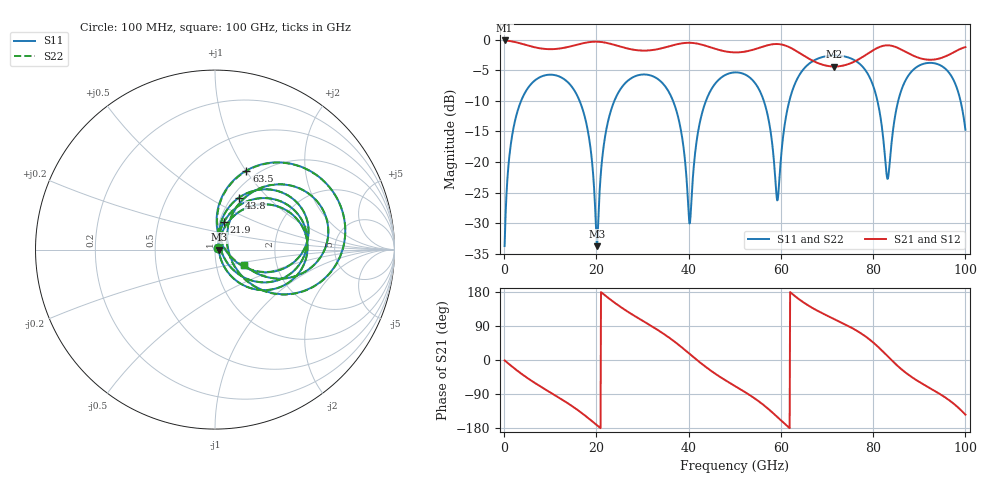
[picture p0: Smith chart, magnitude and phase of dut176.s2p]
! Touchstone file exported from HFSS 2026.1.0
!  File:  C:/ffzhzh/LocalFiles/Ansys_Project_Files/temp_test_TSV_RDL_176_1783474584_48356.aedt
!  Generated:  09:47:24 AM Jul  8, 2026
!  Design:  TSV_RDL
!  Project:  temp_test_TSV_RDL_176_1783474584_48356
! Variables:
!  h_bsmrdl = 3.29um
!  h_ox = 20um
!  h_rdl = 5um
!  h_sub = 71.26um
!  h_tmrdl = 2.49um
!  h_tsv = 71.26um
!  h_via = 3um
!  l_bsmrdl = 349.83um
!  l_sub = 2814um
!  l_tmrdl = 313.58um
!  m_sub = 200um
!  pitch = 45.72um
!  r_tsv = 9.64um
!  s_tmrdl = 10um
!  w_bsmrdl = 20.47um
!  w_sub = 500um
!  w_tmrdl = 16.26um
!  x_tsv_center1 = 321.71um
!  x_tsv_center2 = 692.01um
!  x_tsv_center3 = 1021.85um
!  x_tsv_center4 = 1392.15um
!  x_tsv_center5 = 1721.99um
!  x_tsv_center6 = 2092.29um
# GHz S MA R 50.000000
! Terminal data exported
! Port[1] = TM_RDL1_1_T1
! Port[2] = TM_RDL5_1_T1
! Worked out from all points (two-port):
!   1000 points, 100 MHz to 100 GHz, reference 50 ohm
!   highest |S21| = -0.16 dB at 100 MHz (marker M1); lowest = -4.4 dB at 71.6 GHz (marker M2)
!   |S21| within 3 dB of the highest: start of sweep to 66.13 GHz; 77.05 GHz to 90.65 GHz (13.61 GHz wide, 16.2 % of centre) (the widest 2 of 3)
!   lowest |S11| = -33.8 dB at 20.1 GHz (marker M3), VSWR 1.04, Z = 52.1 + j0.0505 ohm
!   |S11| at or under -10 dB: 16.35 GHz to 23.91 GHz (7.562 GHz wide, 37.6 % of centre); 36.6 GHz to 43.76 GHz (7.157 GHz wide, 17.8 % of centre); 56.28 GHz to 61.84 GHz (5.558 GHz wide, 9.41 % of centre) (the widest 3 of 6)
!   |S22| runs from -33.9 to -2.6 dB; largest |S21 - S12| = 3.1e-10
!   S11 on the Smith chart (normalised r, x): 100 MHz: 1.04, +0.02; 21.9 GHz: 1.05, +0.33; 43.8 GHz: 1.08, +0.69; 63.5 GHz: 0.89, +1.01; 100 GHz: 1.36, -0.24
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0.1  0.02054 29.6  0.9823 -1.1  0.9823 -1.1  0.02054 29.6
! Gamma 0 0 0 0
! Port Impedance 50 0 50 0
1.7  0.1617 65.0  0.9648 -17.1  0.9648 -17.1  0.1617 65.0
4.9  0.3885 40.4  0.8983 -46.3  0.8983 -46.3  0.3885 40.3
10.7  0.5141 -2.0  0.8348 -90.5  0.8348 -90.5  0.5141 -2.0
16.8  0.2849 -48.1  0.9268 -139.8  0.9268 -139.8  0.2849 -48.1
20.1  0.02051 1.4  0.9597 -171.9  0.9597 -171.9  0.0201 1.0
21.9  0.1627 71.9  0.9434 170.3  0.9434 170.3  0.1625 72.1
33.4  0.4731 -11.2  0.8355 78.5  0.8355 78.5  0.473 -11.1
37.7  0.2341 -43.1  0.9181 41.3  0.9181 41.3  0.2341 -43.0
40.2  0.03139 10.8  0.94 16.3  0.94 16.3  0.03183 11.0
43.8  0.3191 65.2  0.8862 -19.1  0.8862 -19.1  0.3192 65.2
50.1  0.539 20.1  0.7846 -69.1  0.7846 -69.1  0.539 20.1
56.1  0.331 -22.3  0.8748 -117.4  0.8748 -117.4  0.3313 -21.9
59.2  0.04851 22.9  0.9188 -150.0  0.9188 -150.0  0.05103 23.1
63.5  0.4737 68.4  0.7986 164.3  0.7986 164.3  0.4739 68.1
66.7  0.6582 45.3  0.6769 138.3  0.6769 138.3  0.6583 45.1
71.6  0.7412 17.3  0.6015 107.8  0.6015 107.8  0.7412 17.1
79.3  0.4858 -30.6  0.7869 53.4  0.7869 53.4  0.4856 -30.8
83.4  0.08237 34.9  0.8957 6.7  0.8957 6.7  0.08059 35.6
85.8  0.3543 58.8  0.8386 -20.9  0.8386 -20.9  0.3541 59.0
89.8  0.6075 31.0  0.7103 -56.3  0.7103 -56.3  0.6075 31.0
100  0.1833 -27.5  0.8664 -144.1  0.8664 -144.1  0.1837 -27.4
